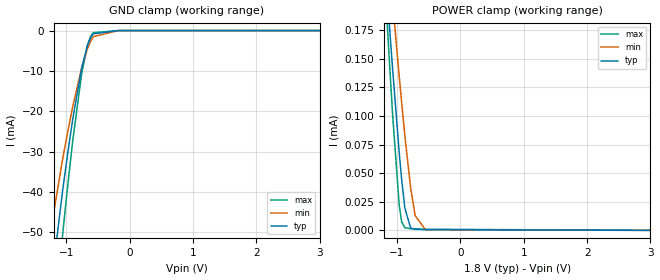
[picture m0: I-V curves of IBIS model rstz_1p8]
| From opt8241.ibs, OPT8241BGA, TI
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|   rstz_1p8 Model
[Model]   rstz_1p8
Model_type   Input
Vinl = 0.54
Vinh = 1.26
|   typ   min   max
|   (nom PVT)   (fast PVT)   (slow PVT)
C_comp   2.094e-12   1.903e-12   2.287e-12
[Model spec]
|subparameter
Vinl   0.54   0.51   0.57
Vinh   1.26   1.19   1.33
| Where nom  PVT is Nominal Process, 1.8V, 27C
|   Fast PVT is Strong Process,  1.9V, -40C
|   Slow PVT is Weak Process,   1.7V, 125C
[Voltage Range]   1.8   1.7   1.9
|Junction Temperature
[Temperature Range]   27   125   -40
[Power Clamp Reference]   1.8   1.7   1.9
[GND Clamp Reference]   0   0   0
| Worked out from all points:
|   GND clamp passes 1 mA (typ) near -0.58 V on its own axis
[GND Clamp]
|   Voltage   I(typ)   I(min)   I(max)
-1.8V     -235.1mA   -133.1mA   -339.3mA
-1.305V   -71.83mA   -55.34mA   -91.7mA
-1.063V   -40.55mA   -32.52mA   -51.65mA
-1.044V   -38.27mA   -30.86mA   -48.69mA
-973.8mV  -30.2mA    -24.94mA   -38.14mA
-896.4mV  -21.94mA   -18.83mA   -27.26mA
-756mV    -9.362mA   -9.239mA   -10.69mA
-665.7mV  -3.75mA    -4.562mA   -3.604mA
-613.4mV  -1.737mA   -2.608mA   -1.375mA
-572.4mV  -810.3uA   -1.519mA   -523.9uA
-180mV    -497.4nA   -564.7nA   -770.9nA
3.6V      0A         0A         0A
[POWER Clamp]
|   Voltage   I(typ)   I(min)   I(max)
-1.8V     735.1uA    693.3uA    857.7uA
-1.206V   246.5uA    288.5uA    232.3uA
-1.163V   212.5uA    260.1uA    189.5uA
-1.122V   180.7uA    233.3uA    149.7uA
-1.069V   141uA      199.5uA    100.9uA
-964.8mV  67.65uA    134.4uA    21.86uA
-926mV    44.02uA    111.2uA    7.444uA
-874.7mV  19.16uA    81.96uA    2.325uA
-785.1mV  2.297uA    37.3uA     1.574uA
-713.7mV  1.064uA    12.95uA    1.402uA
-550.5mV  726.2nA    684.1nA    1.037uA
3.6V      0A         0A         0A
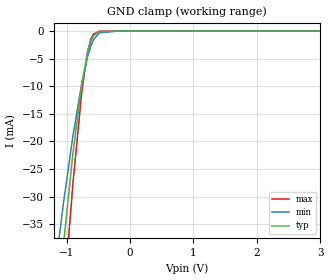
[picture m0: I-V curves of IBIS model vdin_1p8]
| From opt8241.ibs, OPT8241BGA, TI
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|   vdin_1p8 Model
[Model]   vdin_1p8
Model_type   Input
Vinl = 0.54
Vinh = 1.26
|   typ   min   max
|   (nom PVT)   (fast PVT)   (slow PVT)
C_comp   2.094e-12   1.893e-12   2.287e-12
[Model spec]
|subparameter
Vinl   0.54   0.51   0.57
Vinh   1.26   1.19   1.33
| Where nom  PVT is Nominal Process, 1.8V, 27C
|   Fast PVT is Strong Process,  1.9V, -40C
|   Slow PVT is Weak Process,   1.7V, 125C
[Voltage Range]   1.8   1.7   1.9
|Junction Temperature
[Temperature Range]   27   125   -40
[Power Clamp Reference]   1.8   1.7   1.9
[GND Clamp Reference]   0   0   0
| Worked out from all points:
|   GND clamp passes 1 mA (typ) near -0.58 V on its own axis
[GND Clamp]
|   Voltage   I(typ)   I(min)   I(max)
-1.8V     -238.3mA   -133.6mA   -345.3mA
-1.276V   -67.82mA   -52.41mA   -86.62mA
-1.069V   -41.29mA   -33.06mA   -52.62mA
-1.048V   -38.72mA   -31.19mA   -49.28mA
-900mV    -22.3mA    -19.1mA    -27.74mA
-757.8mV  -9.497mA   -9.346mA   -10.86mA
-665.7mV  -3.749mA   -4.562mA   -3.604mA
-615.1mV  -1.787mA   -2.661mA   -1.424mA
-572.4mV  -809.9uA   -1.519mA   -523.2uA
-480.8mV  -92.99uA   -320.3uA   -34.6uA
-180mV    0A         -238.8nA   0A
3.6V      0A         0A         0A
[POWER Clamp]
|   Voltage   I(typ)   I(min)   I(max)
-1.8V     0A         0A         0A
0V        0A         0A         0A
3.6V      0A         0A         0A
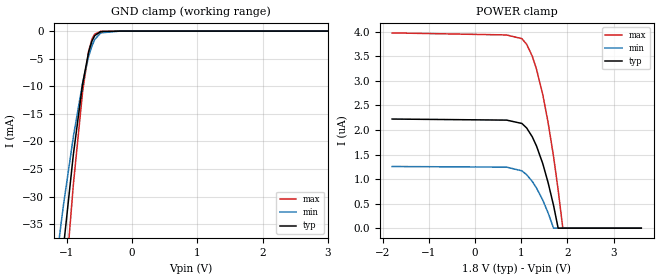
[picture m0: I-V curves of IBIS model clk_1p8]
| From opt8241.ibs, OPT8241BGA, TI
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|   clk_1p8 Model
[Model]   clk_1p8
Model_type   Input
Vinl = 0.54
Vinh = 1.26
|   typ   min   max
|   (nom PVT)   (fast PVT)   (slow PVT)
C_comp   2.106e-12   1.914e-12   2.287e-12
[Model spec]
|subparameter
Vinl   0.54   0.51   0.57
Vinh   1.26   1.19   1.33
| Where nom  PVT is Nominal Process, 1.8V, 27C
|   Fast PVT is Strong Process,  1.9V, -40C
|   Slow PVT is Weak Process,   1.7V, 125C
[Voltage Range]   1.8   1.7   1.9
|Junction Temperature
[Temperature Range]   27   125   -40
[Power Clamp Reference]   1.8   1.7   1.9
[GND Clamp Reference]   0   0   0
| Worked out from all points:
|   GND clamp passes 1 mA (typ) near -0.58 V on its own axis
[GND Clamp]
|   Voltage   I(typ)   I(min)   I(max)
-1.8V     -238.3mA   -133.6mA   -345.3mA
-1.276V   -67.82mA   -52.41mA   -86.63mA
-1.069V   -41.3mA    -33.07mA   -52.62mA
-1.048V   -38.73mA   -31.19mA   -49.28mA
-900mV    -22.31mA   -19.1mA    -27.74mA
-757.8mV  -9.5mA     -9.348mA   -10.87mA
-665.7mV  -3.752mA   -4.563mA   -3.609mA
-615.1mV  -1.79mA    -2.663mA   -1.43mA
-572.4mV  -813uA     -1.52mA    -528.5uA
-480.8mV  -95.75uA   -321.8uA   -39.24uA
-180mV    -948.6nA   -786.6nA   -1.575uA
3.6V      0A         0A         0A
[POWER Clamp]
|   Voltage   I(typ)   I(min)   I(max)
-1.8V     2.223uA    1.256uA    3.978uA
682mV     2.201uA    1.243uA    3.936uA
1.012V    2.133uA    1.168uA    3.86uA
1.115V    2.042uA    1.089uA    3.747uA
1.238V    1.86uA     950.8nA    3.502uA
1.33V     1.671uA    815.9nA    3.236uA
1.466V    1.311uA    568.1nA    2.715uA
1.58V     928.5nA    312.4nA    2.153uA
1.699V    460.9nA    0A         1.457uA
1.798V    0A         0A         779.4nA
1.899V    0A         0A         0A
3.6V      0A         0A         0A
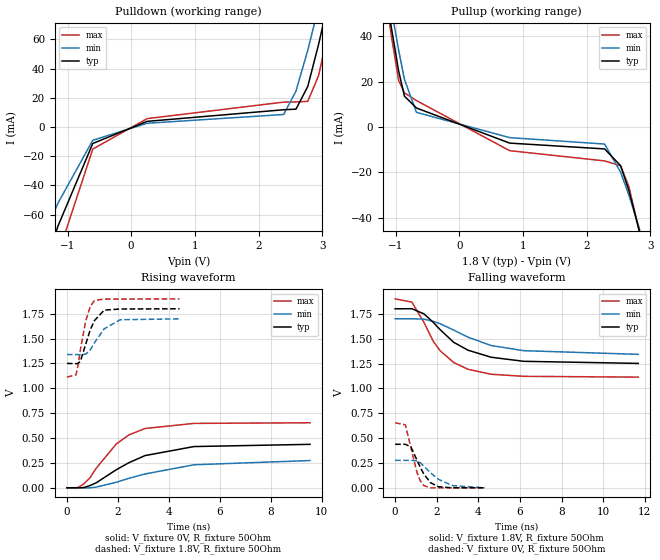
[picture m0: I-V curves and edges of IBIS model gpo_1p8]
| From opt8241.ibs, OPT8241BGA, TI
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|   gpo_1p8 Model
[Model]   gpo_1p8
Model_type   Output
Polarity   Non-Inverting
Vmeas = 0.9
Vref = 0
Cref = 2pF
Rref = 200
|   typ   min   max
|   (nom PVT)   (fast PVT)   (slow PVT)
C_comp   2.206e-12   2.001e-12   2.430e-12
| Where nom  PVT is Nominal Process, 1.8V, 27C
|   Fast PVT is Strong Process,  1.9V, -40C
|   Slow PVT is Weak Process,   1.7V, 125C
[Voltage Range]   1.8   1.7   1.9
|Junction Temperature
[Temperature Range]   27   125   -40
[Pullup Reference]   1.8   1.7   1.9
[Pulldown Reference]   0   0   0
[Power Clamp Reference]   1.8   1.7   1.9
[GND Clamp Reference]   0   0   0
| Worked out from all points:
|   slope of the pulldown table from 0 to 0.27 V, typ, clamps not added: 64.6 ohm
|   slope of the pullup table from 0 to 0.27 V, typ, clamps not added: 92.4 ohm
|   falling waveform, V_fixture 1.8V, R_fixture 50Ohm: 20-80 % time 2.08ns typ, 2.63ns min, 1.53ns max; typ from 1.8 V to 1.25 V
|   rising waveform, V_fixture 0V, R_fixture 50Ohm: 20-80 % time 2ns typ, 2.68ns min, 1.39ns max; typ from 0 V to 0.437 V
|   rising waveform, V_fixture 1.8V, R_fixture 50Ohm: 20-80 % time 451ps typ, 613ps min, 346ps max; typ from 1.25 V to 1.8 V
|   falling waveform, V_fixture 0V, R_fixture 50Ohm: 20-80 % time 641ps typ, 956ps min, 455ps max; typ from 0.437 V to 0 V
[Pulldown]
|   Voltage   I(typ)   I(min)   I(max)
-1.8V     -225.4mA   -143.8mA   -304.1mA
-1.47V    -113.7mA   -86.18mA   -142.8mA
-1.256V   -82.56mA   -62.97mA   -105.6mA
-1.152V   -68.03mA   -52.26mA   -87.72mA
-603.2mV  -11.23mA   -9.042mA   -15.07mA
250.2mV   3.907mA    2.602mA    5.787mA
2.394V    11.86mA    8.618mA    17.09mA
2.588V    12.27mA    24.6mA     17.22mA
2.773V    27.78mA    52.65mA    17.61mA
2.942V    56.45mA    82.16mA    35.09mA
3.07V     80.77mA    105mA      60.11mA
3.6V      185.5mA    195.8mA    177.6mA
[Pullup]
|   Voltage   I(typ)   I(min)   I(max)
-1.8V     185.8mA    179.6mA    199.1mA
-1.134V   55.78mA    63.3mA     53.53mA
-1.067V   43.59mA    51.95mA    39.88mA
-954.5mV  24.76mA    33.93mA    20.59mA
-863.3mV  13.65mA    21.05mA    15.1mA
-674.6mV  8.417mA    6.495mA    11.69mA
789.1mV   -7.076mA   -4.658mA   -10.42mA
2.28V     -9.646mA   -7.498mA   -14.93mA
2.531V    -17.04mA   -19.87mA   -17.07mA
2.661V    -27.87mA   -29.99mA   -26.17mA
2.828V    -46.12mA   -44.98mA   -46.37mA
3.6V      -218.4mA   -181.2mA   -239mA
[Ramp]
R_load = 50
|   typ   min   max
dV/dt_r   0.262388/2.00011e-09   0.165723/2.72562e-09  0.392287/1.3872e-09
dV/dt_f   0.329703/2.07923e-09   0.21601/2.64824e-09   0.472263/1.5328e-09
[Falling Waveform]
V_fixture = 1.8V
V_fixture_min = 1.7V
V_fixture_max = 1.9V
R_fixture = 50Ohm
|   Time   V(typ)   V(min)   V(max)
0s        1.8V       1.7V       1.9V
805ps     1.801V     1.7V       1.867V
1.385ns   1.749V     1.696V     1.663V
1.835ns   1.663V     1.674V     1.472V
2.16ns    1.591V     1.65V      1.379V
2.815ns   1.463V     1.586V     1.26V
3.5ns     1.384V     1.515V     1.192V
4.615ns   1.313V     1.431V     1.142V
6.175ns   1.272V     1.379V     1.121V
11.69ns   1.251V     1.342V     1.113V
[Rising Waveform]
V_fixture = 0V
V_fixture_min = 0V
V_fixture_max = 0V
R_fixture = 50Ohm
|   Time   V(typ)   V(min)   V(max)
0s        442pV      24.69nV    234.8pV
410ps     -532uV     139.8uV    196.7uV
655ps     1.711mV    -589.5uV   36.51mV
905ps     22.11mV    -933uV     99.63mV
1.145ns   49.02mV    6.045mV    194.9mV
1.935ns   180.6mV    55.02mV    439.4mV
2.43ns    251.8mV    94.54mV    531.2mV
3.07ns    323.8mV    138.8mV    596.2mV
4.99ns    414.4mV    231.2mV    647.4mV
9.55ns    436.8mV    273.8mV    653.7mV
[Rising Waveform]
V_fixture = 1.8V
V_fixture_min = 1.7V
V_fixture_max = 1.9V
R_fixture = 50Ohm
|   Time   V(typ)   V(min)   V(max)
0s        1.251V     1.34V      1.113V
355ps     1.248V     1.34V      1.136V
435ps     1.25V      1.339V     1.229V
530ps     1.274V     1.338V     1.391V
740ps     1.446V     1.344V     1.68V
920ps     1.592V     1.388V     1.826V
1.085ns   1.683V     1.46V      1.884V
1.465ns   1.787V     1.599V     1.898V
2.095ns   1.798V     1.69V      1.898V
4.425ns   1.8V       1.699V     1.9V
[Falling Waveform]
V_fixture = 0V
V_fixture_min = 0V
V_fixture_max = 0V
R_fixture = 50Ohm
|   Time   V(typ)   V(min)   V(max)
0s        437.3mV    276.2mV    654mV
490ps     437.9mV    276.1mV    633.4mV
755ps     410.7mV    276.7mV    405.8mV
1.05ns    277.9mV    271.4mV    154.6mV
1.205ns   207.5mV    251.7mV    71.52mV
1.37ns    141.6mV    219.3mV    23.76mV
1.695ns   52.25mV    152.1mV    -395.4uV
2.085ns   10.12mV    85.17mV    -408.6uV
2.75ns    108.6uV    21.92mV    405.3uV
4.3ns     201.7uV    434.8uV    43.6uV
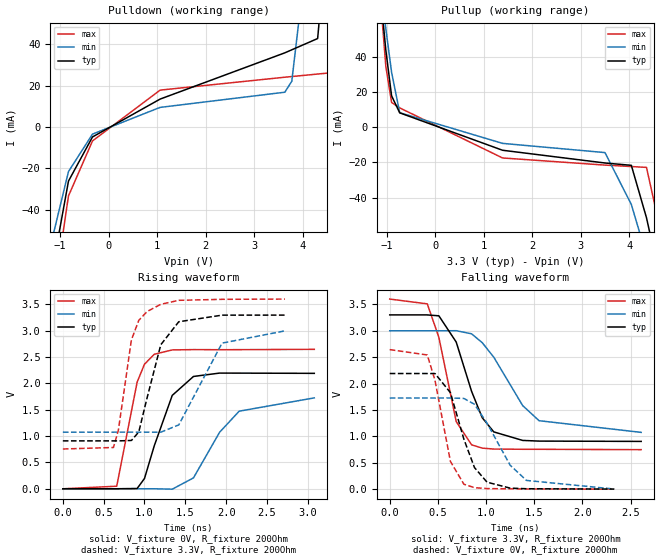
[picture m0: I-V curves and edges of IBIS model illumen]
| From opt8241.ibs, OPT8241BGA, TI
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|   illumen Model
[Model]   illumen
Model_type   Output
Polarity   Non-Inverting
Vmeas = 1.65
Vref = 0
Cref = 2pF
Rref = 200
|   typ   min   max
|   (nom PVT)   (fast PVT)   (slow PVT)
C_comp   2.058e-12   1.793e-12   2.300e-12
| Where nom  PVT is Nominal Process, 3.3V, 27C
|   Fast PVT is Strong Process,  3.6V, -40C
|   Slow PVT is Weak Process,   3V, 125C
[Voltage Range]   3.3   3   3.6
|Junction Temperature
[Temperature Range]   27   125   -40
[Pullup Reference]   3.3   3   3.6
[Pulldown Reference]   0   0   0
[Power Clamp Reference]   3.3   3   3.6
[GND Clamp Reference]   0   0   0
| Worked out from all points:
|   slope of the pulldown table from 0 to 0.495 V, typ, clamps not added: 71.8 ohm
|   slope of the pullup table from 0 to 0.495 V, typ, clamps not added: 95.4 ohm
|   falling waveform, V_fixture 3.3V, R_fixture 200Ohm: 20-80 % time 270ps typ, 406ps min, 197ps max; typ from 3.3 V to 0.906 V
|   rising waveform, V_fixture 0V, R_fixture 200Ohm: 20-80 % time 280ps typ, 430ps min, 194ps max; typ from 0 V to 2.19 V
|   rising waveform, V_fixture 3.3V, R_fixture 200Ohm: 20-80 % time 240ps typ, 348ps min, 179ps max; typ from 0.908 V to 3.29 V
|   falling waveform, V_fixture 0V, R_fixture 200Ohm: 20-80 % time 227ps typ, 330ps min, 166ps max; typ from 2.19 V to 0.004 V
[Pulldown]
|   Voltage   I(typ)   I(min)   I(max)
-3.3V     -1.429A    -1.241A    -1.581A
-1.722V   -185.3mA   -117.5mA   -268.3mA
-1.468V   -109.3mA   -83.9mA    -135.8mA
-825mV    -26.11mA   -21.5mA    -33.3mA
-330mV    -4.75mA    -3.377mA   -6.679mA
1.063V    13.57mA    9.553mA    17.91mA
3.633V    35.95mA    16.9mA     24.16mA
3.777V    37.42mA    22.19mA    24.48mA
4.31V     42.88mA    128.7mA    25.69mA
4.598V    119mA      196mA      26.34mA
4.97V     224.1mA    280.8mA    146.2mA
6.6V      699.7mA    673.8mA    732.4mA
[Pullup]
|   Voltage   I(typ)   I(min)   I(max)
-3.3V     703.4mA    604.2mA    845.2mA
-1.77V    257.9mA    235.9mA    294.5mA
-1.021V   43.73mA    55.8mA     34.52mA
-902.4mV  17.79mA    31.19mA    14.01mA
-735mV    8.123mA    8.213mA    10.94mA
1.384V    -13.14mA   -9.229mA   -17.52mA
3.495V    -20.38mA   -14.47mA   -21.58mA
4.038V    -21.71mA   -43.96mA   -22.4mA
4.35V     -51.47mA   -72.96mA   -22.88mA
4.608V    -83.59mA   -100.1mA   -54.87mA
4.811V    -111.2mA   -149.2mA   -86.36mA
6.6V      -1.426A    -1.474A    -1.322A
[Ramp]
R_load = 200
|   typ   min   max
dV/dt_r   1.3166/2.81454e-10   1.03727/4.30517e-10   1.58757/1.94145e-10
dV/dt_f   1.44014/2.70555e-10   1.15809/4.07283e-10   1.71258/1.97067e-10
[Falling Waveform]
V_fixture = 3.3V
V_fixture_min = 3V
V_fixture_max = 3.6V
R_fixture = 200Ohm
|   Time   V(typ)   V(min)   V(max)
0s        3.3V       3V         3.6V
390ps     3.3V       3V         3.509V
510ps     3.283V     3V         2.876V
690ps     2.787V     3.001V     1.282V
850ps     1.852V     2.942V     841.3mV
960ps     1.355V     2.775V     779mV
1.08ns    1.086V     2.5V       761.2mV
1.38ns    924.6mV    1.584V     757.1mV
1.55ns    911.9mV    1.298V     756.6mV
2.61ns    906mV      1.077V     749.9mV
[Rising Waveform]
V_fixture = 0V
V_fixture_min = 0V
V_fixture_max = 0V
R_fixture = 200Ohm
|   Time   V(typ)   V(min)   V(max)
0s        1.275nV    35.58nV    828.6pV
660ps     290.9uV    -5.246uV   48.7mV
910ps     5.607mV    39.74uV    2.022V
1ns       195.2mV    181.8uV    2.362V
1.12ns    815.7mV    211.7uV    2.55V
1.34ns    1.77V      -7.438mV   2.632V
1.6ns     2.129V     206.2mV    2.638V
1.92ns    2.193V     1.071V     2.636V
2.16ns    2.192V     1.471V     2.637V
3.08ns    2.188V     1.723V     2.643V
[Rising Waveform]
V_fixture = 3.3V
V_fixture_min = 3V
V_fixture_max = 3.6V
R_fixture = 200Ohm
|   Time   V(typ)   V(min)   V(max)
0s        907.9mV    1.073V     753.9mV
620ps     907.9mV    1.073V     782.8mV
680ps     907.6mV    1.074V     1.111V
840ps     915.9mV    1.074V     2.824V
930ps     1.077V     1.073V     3.192V
1.03ns    1.713V     1.073V     3.358V
1.2ns     2.731V     1.073V     3.497V
1.42ns    3.166V     1.211V     3.572V
1.95ns    3.291V     2.761V     3.591V
2.72ns    3.292V     2.993V     3.596V
[Falling Waveform]
V_fixture = 0V
V_fixture_min = 0V
V_fixture_max = 0V
R_fixture = 200Ohm
|   Time   V(typ)   V(min)   V(max)
0s        2.191V     1.727V     2.643V
390ps     2.191V     1.727V     2.542V
470ps     2.19V      1.727V     2.06V
630ps     1.829V     1.728V     526.8mV
770ps     946.4mV    1.719V     95.53mV
880ps     410.2mV    1.608V     30.04mV
1.01ns    134.1mV    1.251V     13.25mV
1.25ns    21.64mV    455.2mV    8.17mV
1.42ns    10.27mV    167.3mV    6.629mV
2.33ns    3.728mV    4.662mV    2.085mV
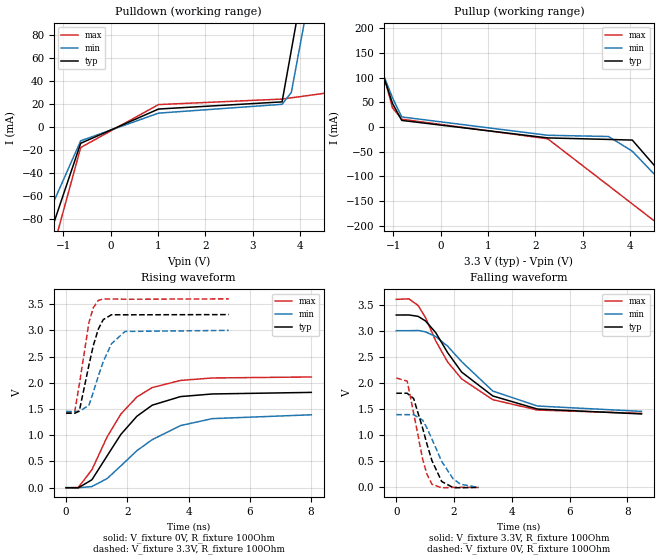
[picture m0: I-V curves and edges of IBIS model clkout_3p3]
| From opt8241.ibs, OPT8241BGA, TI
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|   clkout_3p3 Model
[Model]   clkout_3p3
Model_type   Output
Polarity   Non-Inverting
Vmeas = 1.65
Vref = 0
Cref = 2pF
Rref = 150
|   typ   min   max
|   (nom PVT)   (fast PVT)   (slow PVT)
C_comp   2.130e-12   1.914e-12   2.371e-12
| Where nom  PVT is Nominal Process, 3.3V, 27C
|   Fast PVT is Strong Process,  3.6V, -40C
|   Slow PVT is Weak Process,   3V, 125C
[Voltage Range]   3.3   3   3.6
|Junction Temperature
[Temperature Range]   27   125   -40
[Pullup Reference]   3.3   3   3.6
[Pulldown Reference]   0   0   0
[Power Clamp Reference]   3.3   3   3.6
[GND Clamp Reference]   0   0   0
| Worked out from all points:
|   slope of the pulldown table from 0 to 0.495 V, typ, clamps not added: 56.5 ohm
|   slope of the pullup table from 0 to 0.495 V, typ, clamps not added: 70.7 ohm
|   falling waveform, V_fixture 3.3V, R_fixture 100Ohm: 20-80 % time 1.81ns typ, 1.81ns min, 1.67ns max; typ from 3.3 V to 1.41 V
|   rising waveform, V_fixture 0V, R_fixture 100Ohm: 20-80 % time 1.4ns typ, 1.87ns min, 1.32ns max; typ from 0 V to 1.82 V
|   rising waveform, V_fixture 3.3V, R_fixture 100Ohm: 20-80 % time 426ps typ, 570ps min, 344ps max; typ from 1.42 V to 3.3 V
|   falling waveform, V_fixture 0V, R_fixture 100Ohm: 20-80 % time 571ps typ, 712ps min, 448ps max; typ from 1.8 V to 0.002 V
[Pulldown]
|   Voltage   I(typ)   I(min)   I(max)
-3.3V     -1.592A    -1.388A    -1.755A
-1.956V   -380.3mA   -251.2mA   -493.8mA
-1.791V   -245.8mA   -147.4mA   -346.5mA
-1.656V   -157.1mA   -111.1mA   -233.4mA
-1.478V   -116.7mA   -90.12mA   -144.7mA
-632.4mV  -14.03mA   -11.87mA   -17.7mA
1.013V    15.62mA    12.07mA    19.46mA
3.623V    21.8mA     19.71mA    24.24mA
3.819V    66.55mA    30mA       25.33mA
4.606V    246.5mA    203.8mA    29.72mA
4.926V    319.8mA    281mA      133.7mA
6.6V      702.8mA    676.6mA    735.9mA
[Pullup]
|   Voltage   I(typ)   I(min)   I(max)
-3.3V     708.8mA    609.8mA    850.9mA
-1.021V   47.98mA    59.48mA    39.08mA
-825mV    13.5mA     20.52mA    15.93mA
2.26V     -21.98mA   -16.61mA   -23.78mA
3.546V    -25.06mA   -19.17mA   -118.8mA
4.047V    -26.41mA   -48.96mA   -155.9mA
4.623V    -90.04mA   -106.8mA   -198.5mA
4.737V    -105.5mA   -126.8mA   -206.9mA
4.851V    -122mA     -179.2mA   -215.3mA
4.917V    -136.1mA   -222.6mA   -220.2mA
5.092V    -240.3mA   -354.5mA   -233.1mA
6.6V      -1.589A    -1.651A    -1.466A
[Ramp]
R_load = 100
|   typ   min   max
dV/dt_r   1.08948/1.39353e-09   0.83861/1.88597e-09   1.26613/1.31948e-09
dV/dt_f   1.13769/1.81666e-09   0.931834/1.82974e-09   1.30827/1.66723e-09
[Falling Waveform]
V_fixture = 3.3V
V_fixture_min = 3V
V_fixture_max = 3.6V
R_fixture = 100Ohm
|   Time   V(typ)   V(min)   V(max)
0s        3.3V       3V         3.6V
436ps     3.301V     3V         3.609V
754ps     3.275V     3.005V     3.483V
1.01ns    3.187V     2.978V     3.253V
1.364ns   2.964V     2.887V     2.805V
1.776ns   2.581V     2.705V     2.402V
2.262ns   2.208V     2.407V     2.078V
3.34ns    1.751V     1.845V     1.68V
4.882ns   1.501V     1.559V     1.482V
8.484ns   1.407V     1.456V     1.418V
[Rising Waveform]
V_fixture = 0V
V_fixture_min = 0V
V_fixture_max = 0V
R_fixture = 100Ohm
|   Time   V(typ)   V(min)   V(max)
0s        867.6pV    33.8nV     522.3pV
398ps     -2.799mV   105.7uV    3.906mV
844ps     151.8mV    21.8mV     343.2mV
1.342ns   609.2mV    174.7mV    971.5mV
1.79ns    1.017V     417.2mV    1.405V
2.312ns   1.362V     705.4mV    1.73V
2.812ns   1.573V     916.1mV    1.909V
3.736ns   1.737V     1.184V     2.045V
4.774ns   1.787V     1.317V     2.092V
8.008ns   1.817V     1.39V      2.111V
[Rising Waveform]
V_fixture = 3.3V
V_fixture_min = 3V
V_fixture_max = 3.6V
R_fixture = 100Ohm
|   Time   V(typ)   V(min)   V(max)
0s        1.42V      1.454V     1.431V
282ps     1.419V     1.454V     1.453V
432ps     1.462V     1.454V     1.966V
748ps     2.343V     1.574V     3.154V
890ps     2.712V     1.822V     3.434V
1.054ns   3.025V     2.132V     3.571V
1.214ns   3.205V     2.404V     3.599V
1.482ns   3.297V     2.745V     3.598V
1.926ns   3.296V     2.979V     3.593V
5.312ns   3.3V       2.999V     3.6V
[Falling Waveform]
V_fixture = 0V
V_fixture_min = 0V
V_fixture_max = 0V
R_fixture = 100Ohm
|   Time   V(typ)   V(min)   V(max)
0s        1.803V     1.394V     2.095V
376ps     1.803V     1.394V     2.035V
600ps     1.704V     1.394V     1.424V
916ps     1.128V     1.287V     534.8mV
1.064ns   824.8mV    1.136V     249.5mV
1.234ns   514mV      926mV      61.55mV
1.572ns   114.6mV    497.5mV    -6.876mV
1.974ns   -3.272mV   159.8mV    2.209mV
2.234ns   -4.865mV   60.08mV    2.876mV
2.856ns   2.118mV    1.553mV    1.05mV
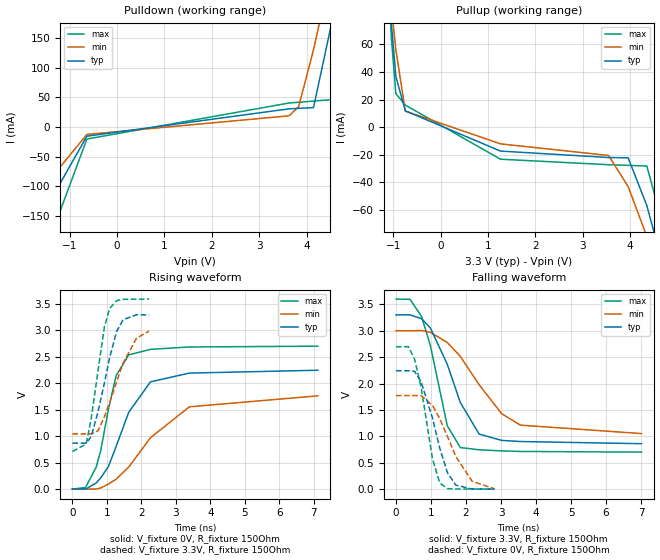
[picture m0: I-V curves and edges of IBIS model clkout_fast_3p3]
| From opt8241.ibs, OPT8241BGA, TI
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|   clkout_fast_3p3 Model
[Model]   clkout_fast_3p3
Model_type   Output
Polarity   Non-Inverting
Vmeas = 1.65
Vref  = 0
Cref  = 2pF
Rref  = 150
|   typ   min   max
|   (nom PVT)   (fast PVT)   (slow PVT)
C_comp   2.118e-12   1.852e-12   2.357e-12
| Where nom  PVT is Nominal Process, 3.3V, 27C
|   Fast PVT is Strong Process,  3.6V, -40C
|   Slow PVT is Weak Process,   3V, 125C
[Voltage Range]   3.3   3   3.6
|Junction Temperature
[Temperature Range]   27   125   -40
[Pullup Reference]   3.3   3   3.6
[Pulldown Reference]   0   0   0
[Power Clamp Reference]   3.3   3   3.6
[GND Clamp Reference]   0   0   0
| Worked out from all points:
|   slope of the pulldown table from 0 to 0.495 V, typ, clamps not added: 50.4 ohm
|   slope of the pullup table from 0 to 0.495 V, typ, clamps not added: 66.6 ohm
|   falling waveform, V_fixture 3.3V, R_fixture 150Ohm: 20-80 % time 837ps typ, 1.28ns min, 568ps max; typ from 3.3 V to 0.861 V
|   rising waveform, V_fixture 0V, R_fixture 150Ohm: 20-80 % time 854ps typ, 1.43ns min, 525ps max; typ from 0 V to 2.25 V
|   rising waveform, V_fixture 3.3V, R_fixture 150Ohm: 20-80 % time 503ps typ, 643ps min, 383ps max; typ from 0.867 V to 3.29 V
|   falling waveform, V_fixture 0V, R_fixture 150Ohm: 20-80 % time 537ps typ, 727ps min, 404ps max; typ from 2.24 V to 0.002 V
[Pulldown]
|   Voltage   I(typ)   I(min)   I(max)
-3.3V     -1.689A    -1.476A    -1.859A
-1.953V   -392.4mA   -256.2mA   -511.3mA
-1.741V   -212.5mA   -128.9mA   -311.9mA
-1.659V   -159.5mA   -111.9mA   -240mA
-636mV    -15.24mA   -12.29mA   -20.09mA
3.633V    30.87mA    19.13mA    40.69mA
3.834V    31.66mA    34.57mA    41.97mA
4.148V    32.91mA    130.4mA    43.97mA
4.498V    163.3mA    256.7mA    46.19mA
4.616V    207.6mA    300.7mA    46.95mA
4.831V    315.1mA    380.5mA    188.6mA
6.6V      1.225A     1.047A     1.541A
[Pullup]
|   Voltage   I(typ)   I(min)   I(max)
-3.3V     1.23A      937mA      1.78A
-1.241V   171.9mA    160.5mA    203.9mA
-1.039V   75.18mA    87.58mA    64.89mA
-943.8mV  36.69mA    56.01mA    24.26mA
-744mV    11.82mA    11.62mA    15.98mA
1.265V    -17.34mA   -12.11mA   -23.22mA
3.546V    -22mA      -20.51mA   -27.21mA
3.96V     -22.24mA   -43.08mA   -27.69mA
4.354V    -56.84mA   -79.17mA   -28.16mA
4.633V    -92.1mA    -109mA     -63.38mA
4.854V    -123.2mA   -184.5mA   -98.16mA
6.6V      -1.686A    -1.757A    -1.55A
[Ramp]
R_load = 150
|   typ   min   max
dV/dt_r   1.34763/8.49556e-10   1.06462/1.44006e-09   1.6209/5.23383e-10
dV/dt_f   1.46281/8.32433e-10   1.17593/1.29164e-09   1.73841/5.67517e-10
[Falling Waveform]
V_fixture = 3.3V
V_fixture_min = 3V
V_fixture_max = 3.6V
R_fixture = 150Ohm
|   Time   V(typ)   V(min)   V(max)
0s        3.3V       3V         3.6V
402ps     3.3V       3V         3.595V
730ps     3.229V     3.004V     3.271V
982ps     3.053V     2.97V      2.721V
1.464ns   2.366V     2.779V     1.202V
1.838ns   1.64V      2.514V     787.6mV
2.376ns   1.043V     1.977V     746mV
3.018ns   923.9mV    1.429V     724.8mV
3.552ns   902.4mV    1.213V     714.4mV
7.012ns   861.2mV    1.053V     701.8mV
[Rising Waveform]
V_fixture = 0V
V_fixture_min = 0V
V_fixture_max = 0V
R_fixture = 150Ohm
|   Time   V(typ)   V(min)   V(max)
0s        866pV      37.5nV     485.6pV
380ps     -2.069mV   74.2uV     29.51mV
688ps     113.4mV    1.185mV    412.7mV
820ps     211mV      20.32mV    723.1mV
1.044ns   425.6mV    93.91mV    1.507V
1.268ns   805.2mV    187.8mV    2.146V
1.634ns   1.453V     416.4mV    2.538V
2.266ns   2.028V     971.7mV    2.642V
3.392ns   2.193V     1.555V     2.687V
7.122ns   2.247V     1.763V     2.702V
[Rising Waveform]
V_fixture = 3.3V
V_fixture_min = 3V
V_fixture_max = 3.6V
R_fixture = 150Ohm
|   Time   V(typ)   V(min)   V(max)
0s        867.4mV    1.042V     709.9mV
400ps     868.2mV    1.042V     851.9mV
546ps     997.1mV    1.042V     1.338V
742ps     1.463V     1.102V     2.234V
926ps     2V         1.361V     3.061V
1.078ns   2.483V     1.631V     3.413V
1.284ns   2.981V     2.033V     3.564V
1.47ns    3.203V     2.382V     3.588V
1.862ns   3.296V     2.856V     3.59V
2.226ns   3.292V     2.986V     3.593V
[Falling Waveform]
|Gnd
V_fixture = 0V
V_fixture_min = 0V
V_fixture_max = 0V
R_fixture = 150Ohm
|   Time   V(typ)   V(min)   V(max)
0s        2.243V     1.773V     2.697V
356ps     2.243V     1.773V     2.698V
532ps     2.231V     1.773V     2.46V
718ps     2.034V     1.772V     1.931V
1.044ns   1.343V     1.582V     568mV
1.25ns    776.9mV    1.336V     117.7mV
1.47ns    311.6mV    999.4mV    11.76mV
1.71ns    76.63mV    618.4mV    3.088mV
2.174ns   180.1uV    148.7mV    3.569mV
2.82ns    2.205mV    7.394mV    1.471mV
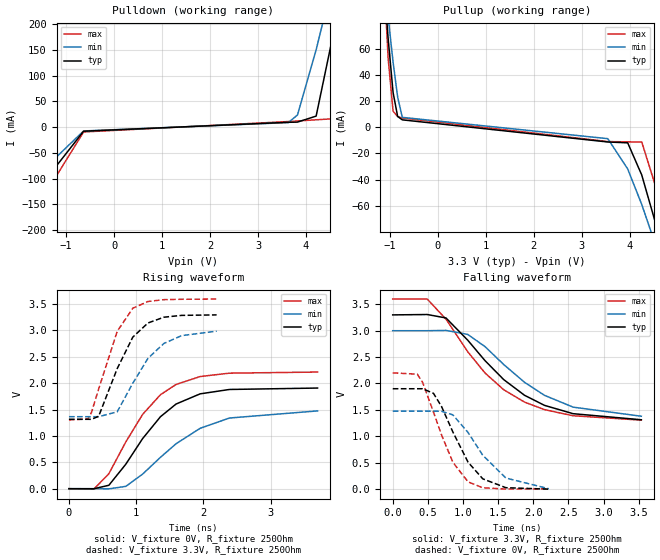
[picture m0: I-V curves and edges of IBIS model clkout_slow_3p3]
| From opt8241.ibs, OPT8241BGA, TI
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|   clkout_slow_3p3 Model
[Model]   clkout_slow_3p3
Model_type   Output
Polarity   Non-Inverting
Vmeas = 1.65
Vref  = 0
Cref  = 2pF
Rref  = 350
|   typ   min   max
|   (nom PVT)   (fast PVT)   (slow PVT)
C_comp   2.143e-12   1.924e-12   2.371e-12
| Where nom  PVT is Nominal Process, 3.3V, 27C
|   Fast PVT is Strong Process,  3.6V, -40C
|   Slow PVT is Weak Process,   3V, 125C
[Voltage Range]   3.3   3   3.6
|Junction Temperature
[Temperature Range]   27   125   -40
[Pullup Reference]   3.3   3   3.6
[Pulldown Reference]   0   0   0
[Power Clamp Reference]   3.3   3   3.6
[GND Clamp Reference]   0   0   0
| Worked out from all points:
|   slope of the pulldown table from 0 to 0.495 V, typ, clamps not added: 125 ohm
|   slope of the pullup table from 0 to 0.495 V, typ, clamps not added: 158 ohm
|   falling waveform, V_fixture 3.3V, R_fixture 250Ohm: 20-80 % time 948ps typ, 938ps min, 914ps max; typ from 3.3 V to 1.31 V
|   rising waveform, V_fixture 0V, R_fixture 250Ohm: 20-80 % time 706ps typ, 901ps min, 688ps max; typ from 0 V to 1.91 V
|   rising waveform, V_fixture 3.3V, R_fixture 250Ohm: 20-80 % time 407ps typ, 489ps min, 364ps max; typ from 1.31 V to 3.29 V
|   falling waveform, V_fixture 0V, R_fixture 250Ohm: 20-80 % time 433ps typ, 501ps min, 381ps max; typ from 1.9 V to -0.004 V
[Pulldown]
|   Voltage   I(typ)   I(min)   I(max)
-3.3V     -1.691A    -1.478A    -1.861A
-1.947V   -381.2mA   -244.1mA   -503.6mA
-1.792V   -245mA     -141mA     -353mA
-1.671V   -157.8mA   -105.8mA   -243.4mA
-1.471V   -107.1mA   -81.93mA   -135mA
-636mV    -7.898mA   -7.402mA   -9.376mA
3.633V    9.393mA    8.858mA    10.86mA
3.822V    9.781mA    23.62mA    11.96mA
4.211V    21.42mA    150mA      14.23mA
4.559V    176.5mA    281.6mA    16.25mA
4.872V    338.5mA    400.1mA    217.8mA
6.6V      1.23A      1.05A      1.546A
[Pullup]
|   Voltage   I(typ)   I(min)   I(max)
-3.3V     1.231A     937.1mA    1.781A
-1.241V   167.8mA    159.4mA    197mA
-1.036V   67.55mA    83.98mA    52.58mA
-933mV    26.45mA    49.6mA     12.19mA
-838.2mV  8.16mA     23mA       8.174mA
-741mV    5.564mA    7.463mA    6.938mA
3.543V    -11.34mA   -8.805mA   -11mA
3.957V    -11.96mA   -31.91mA   -11.23mA
4.25V     -36.54mA   -59.01mA   -11.38mA
4.63V     -85.02mA   -99.87mA   -55.84mA
4.829V    -113.8mA   -160.6mA   -88.71mA
6.6V      -1.69A     -1.76A     -1.556A
[Ramp]
R_load = 250
|   typ   min   max
dV/dt_r   1.14461/7.03914e-10   0.886664/9.02287e-10   1.32636/6.87359e-10
dV/dt_f   1.19792/9.5394e-10   0.98429/9.56025e-10   1.38497/9.2458e-10
[Falling Waveform]
V_fixture = 3.3V
V_fixture_min = 3V
V_fixture_max = 3.6V
R_fixture = 250Ohm
|   Time   V(typ)   V(min)   V(max)
0s        3.3V       3V         3.6V
492ps     3.307V     3V         3.599V
758ps     3.242V     3.006V     3.219V
1.068ns   2.82V      2.93V      2.601V
1.314ns   2.432V     2.698V     2.198V
1.58ns    2.073V     2.359V     1.881V
1.876ns   1.776V     2.022V     1.647V
2.16ns    1.585V     1.775V     1.504V
2.568ns   1.427V     1.551V     1.388V
3.538ns   1.312V     1.379V     1.305V
[Rising Waveform]
V_fixture = 0V
V_fixture_min = 0V
V_fixture_max = 0V
R_fixture = 250Ohm
|   Time   V(typ)   V(min)   V(max)
0s        2.931nV    121nV      1.671nV
370ps     -1.212mV   69.73uV    -9.012mV
594ps     64.65mV    -2.611mV   284.5mV
846ps     463.8mV    43.84mV    886.3mV
1.096ns   948.5mV    276.1mV    1.407V
1.362ns   1.364V     594.7mV    1.781V
1.594ns   1.604V     851.3mV    1.975V
1.952ns   1.797V     1.144V     2.125V
2.388ns   1.88V      1.339V     2.189V
3.7ns     1.907V     1.474V     2.21V
[Rising Waveform]
V_fixture = 3.3V
V_fixture_min = 3V
V_fixture_max = 3.6V
R_fixture = 250Ohm
|   Time   V(typ)   V(min)   V(max)
0s        1.315V     1.364V     1.303V
280ps     1.315V     1.364V     1.321V
334ps     1.314V     1.364V     1.44V
442ps     1.372V     1.364V     1.889V
718ps     2.275V     1.457V     2.981V
950ps     2.872V     1.998V     3.419V
1.176ns   3.14V      2.47V      3.547V
1.412ns   3.249V     2.751V     3.582V
1.676ns   3.284V     2.9V       3.589V
2.198ns   3.293V     2.985V     3.593V
[Falling Waveform]
|Gnd
V_fixture = 0V
V_fixture_min = 0V
V_fixture_max = 0V
R_fixture = 250Ohm
|   Time   V(typ)   V(min)   V(max)
0s        1.9V       1.475V     2.201V
350ps     1.9V       1.475V     2.176V
426ps     1.9V       1.475V     2.02V
580ps     1.813V     1.475V     1.458V
694ps     1.565V     1.473V     1.028V
856ps     1.081V     1.405V     506.2mV
1.072ns   508.2mV    1.071V     134.7mV
1.282ns   192mV      638.8mV    22.72mV
1.61ns    24.49mV    207.6mV    -1.395mV
2.222ns   -3.627mV   4.419mV    2.388mV
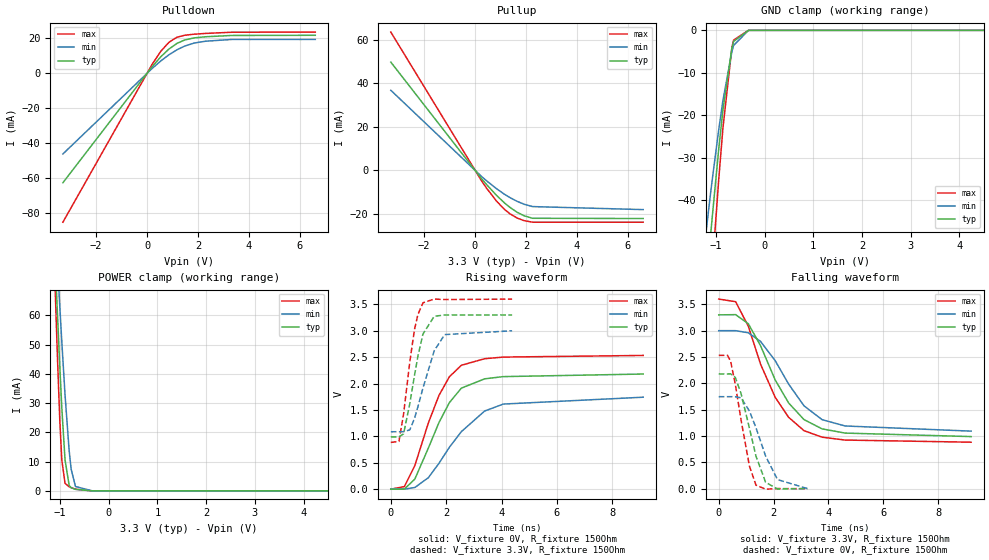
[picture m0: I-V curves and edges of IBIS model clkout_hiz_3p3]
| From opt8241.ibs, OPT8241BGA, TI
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|   clkout_hiz_3p3  Model
[Model]   clkout_hiz_3p3
Model_type   3-state
Polarity   Non-Inverting
Vmeas = 1.65
Vref = 0
Cref = 2pF
Rref = 150
|   typ   min   max
|   (nom PVT)   (fast PVT)   (slow PVT)
C_comp   2.130e-12   1.914e-12   2.371e-12
| Where nom  PVT is Nominal Process, 3.3V, 27C
|   Fast PVT is Strong Process,  3.6V, -40C
|   Slow PVT is Weak Process,   3V, 125C
[Voltage Range]   3.3   3   3.6
|Junction Temperature
[Temperature Range]   27   125   -40
[Pullup Reference]   3.3   3   3.6
[Pulldown Reference]   0   0   0
[Power Clamp Reference]   3.3   3   3.6
[GND Clamp Reference]   0   0   0
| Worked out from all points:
|   slope of the pulldown table from 0 to 0.495 V, typ, clamps not added: 56.5 ohm
|   slope of the pullup table from 0 to 0.495 V, typ, clamps not added: 70.8 ohm
|   POWER clamp passes 1 mA (typ) near -0.76 V on its own axis
|   falling waveform, V_fixture 3.3V, R_fixture 150Ohm: 20-80 % time 1.4ns typ, 1.49ns min, 1.34ns max; typ from 3.3 V to 0.99 V
|   rising waveform, V_fixture 0V, R_fixture 150Ohm: 20-80 % time 1.15ns typ, 1.58ns min, 1.08ns max; typ from 0 V to 2.18 V
|   rising waveform, V_fixture 3.3V, R_fixture 150Ohm: 20-80 % time 481ps typ, 635ps min, 404ps max; typ from 0.991 V to 3.3 V
|   falling waveform, V_fixture 0V, R_fixture 150Ohm: 20-80 % time 610ps typ, 747ps min, 495ps max; typ from 2.18 V to 0.003 V
[Pulldown]
|   Voltage   I(typ)   I(min)   I(max)
-3.3V     -62.74mA   -46.25mA   -85.37mA
206.4mV   3.87mA     2.847mA    5.282mA
537mV     9.429mA    7.033mA    12.56mA
861mV     13.92mA    10.61mA    17.79mA
1.171V    17.1mA     13.45mA    20.65mA
1.473V    19.08mA    15.58mA    21.79mA
1.848V    20.29mA    17.33mA    22.41mA
2.3V      20.95mA    18.4mA     22.85mA
3.324V    21.68mA    19.4mA     23.53mA
6.6V      21.79mA    19.4mA     23.62mA
[GND Clamp]
|   Voltage   I(typ)   I(min)   I(max)
-3.3V     -1.641A    -1.433A    -1.808A
-1.214V   -62.54mA   -48.71mA   -79.99mA
-1.108V   -48.25mA   -38.29mA   -61.64mA
-1.064V   -42.72mA   -34.25mA   -54.47mA
-940.5mV  -27.87mA   -23.35mA   -35.04mA
-855mV    -18.76mA   -16.55mA   -23.01mA
-672mV    -4.274mA   -5.082mA   -4.208mA
-636mV    -2.622mA   -3.546mA   -2.297mA
-330mV    -1.045uA   -12.56uA   -95.92nA
6.6V      0A         0A         0A
[Pullup]
|   Voltage   I(typ)   I(min)   I(max)
-3.3V     49.77mA    36.84mA    63.57mA
252mV     -3.665mA   -2.694mA   -4.646mA
459mV     -6.527mA   -4.79mA    -8.203mA
855mV     -11.56mA   -8.469mA   -14.21mA
1.164V    -14.98mA   -10.99mA   -17.95mA
1.366V    -16.91mA   -12.43mA   -19.87mA
1.657V    -19.23mA   -14.22mA   -21.89mA
1.931V    -20.85mA   -15.53mA   -23.07mA
2.26V     -21.98mA   -16.61mA   -23.78mA
6.6V      -22.1mA    -18mA      -23.78mA
[POWER Clamp]
|   Voltage   I(typ)   I(min)   I(max)
-3.3V     985.5mA    793.3mA    1.299A
-1.122V   87.61mA    99.27mA    81.09mA
-1.086V   73.24mA    87.95mA    62.12mA
-1.049V   59.04mA    76.62mA    43.9mA
-1.005V   42.61mA    63.17mA    24.29mA
-963mV    28.33mA    50.88mA    10.52mA
-897mV    10.62mA    32.8mA     2.616mA
-812.4mV  1.893mA    13.75mA    1.398mA
-771mV    1.105mA    7.398mA    1.104mA
-682.8mV  541.5uA    1.506mA    580.6uA
-330mV    771.2nA    5.113uA    116.9nA
6.6V      0A         0A         0A
[Ramp]
R_load = 150
|   typ   min   max
dV/dt_r   1.30927/1.14921e-09   1.04813/1.58535e-09   1.52033/1.08157e-09
dV/dt_f   1.38832/1.40335e-09   1.14818/1.49284e-09   1.63154/1.34519e-09
[Falling Waveform]
V_fixture = 3.3V
V_fixture_min = 3V
V_fixture_max = 3.6V
R_fixture = 150Ohm
|   Time   V(typ)   V(min)   V(max)
0s        3.3V       3V         3.6V
616ps     3.304V     3V         3.55V
1.078ns   3.132V     2.96V      3.084V
1.526ns   2.713V     2.795V     2.362V
2.058ns   2.064V     2.43V      1.735V
2.548ns   1.627V     1.985V     1.355V
3.108ns   1.312V     1.573V     1.102V
3.766ns   1.136V     1.311V     978.1mV
4.606ns   1.056V     1.191V     923.6mV
9.198ns   989.5mV    1.093V     882.9mV
[Rising Waveform]
V_fixture = 0V
V_fixture_min = 0V
V_fixture_max = 0V
R_fixture = 150Ohm
|   Time   V(typ)   V(min)   V(max)
0s        978.5pV    39.2nV     574.4pV
490ps     1.278mV    -38.54uV   48.82mV
868ps     191.5mV    31.71mV    447.6mV
1.358ns   782.1mV    218.6mV    1.258V
1.736ns   1.259V     487.6mV    1.773V
2.114ns   1.639V     792.7mV    2.128V
2.548ns   1.914V     1.09V      2.347V
3.388ns   2.09V      1.48V      2.471V
4.06ns    2.132V     1.612V     2.502V
9.114ns   2.181V     1.742V     2.533V
[Rising Waveform]
V_fixture = 3.3V
V_fixture_min = 3V
V_fixture_max = 3.6V
R_fixture = 150Ohm
|   Time   V(typ)   V(min)   V(max)
0s        990.9mV    1.088V     885.5mV
294ps     990.7mV    1.088V     905mV
462ps     1.049V     1.088V     1.426V
686ps     1.622V     1.123V     2.414V
854ps     2.15V      1.338V     3.021V
980ps     2.523V     1.563V     3.311V
1.162ns   2.94V      1.918V     3.53V
1.568ns   3.275V     2.623V     3.601V
1.946ns   3.3V       2.928V     3.592V
4.38ns    3.299V     3V         3.6V
[Falling Waveform]
V_fixture = 0V
V_fixture_min = 0V
V_fixture_max = 0V
R_fixture = 150Ohm
|   Time   V(typ)   V(min)   V(max)
0s        2.179V     1.747V     2.532V
322ps     2.179V     1.747V     2.531V
434ps     2.18V      1.747V     2.419V
602ps     2.114V     1.747V     1.991V
812ps     1.809V     1.726V     1.31V
1.12ns    1.147V     1.474V     426.9mV
1.358ns   616.8mV    1.157V     67.13mV
1.708ns   122.9mV    620.1mV    -8.503mV
2.142ns   -5.888mV   173.5mV    2.375mV
3.234ns   2.509mV    2.187mV    764uV
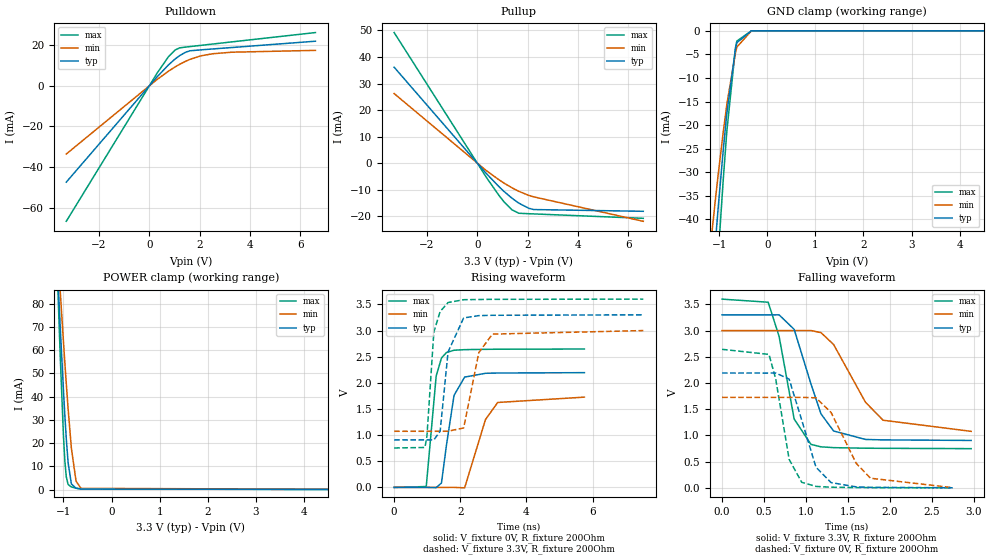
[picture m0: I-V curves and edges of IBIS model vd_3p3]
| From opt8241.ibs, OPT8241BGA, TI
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|   vd_3p3 Model
[Model]   vd_3p3
Model_type   I/O
Polarity   Non-Inverting
Enable   Active-Low
Vinl = 0.99
Vinh = 2.31
Vmeas = 1.65
Vref = 0
Cref = 2pF
Rref = 200
|   typ   min   max
|   (nom PVT)   (fast PVT)   (slow PVT)
C_comp   2.219e-12   1.984e-12   2.430e-12
[Model spec]
|subparameter
Vinl   0.99   0.90   1.08
Vinh   2.31   2.10   2.52
| Where nom  PVT is Nominal Process, 3.3V, 27C
|   Fast PVT is Strong Process,  3.6V, -40C
|   Slow PVT is Weak Process,   3V, 125C
[Voltage Range]   3.3   3   3.6
|Junction Temperature
[Temperature Range]   27   125   -40
[Pullup Reference]   3.3   3   3.6
[Pulldown Reference]   0   0   0
[Power Clamp Reference]   3.3   3   3.6
[GND Clamp Reference]   0   0   0
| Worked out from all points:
|   slope of the pulldown table from 0 to 0.495 V, typ, clamps not added: 71.8 ohm
|   slope of the pullup table from 0 to 0.495 V, typ, clamps not added: 95.4 ohm
|   POWER clamp passes 1 mA (typ) near -0.78 V on its own axis
|   falling waveform, V_fixture 3.3V, R_fixture 200Ohm: 20-80 % time 275ps typ, 410ps min, 200ps max; typ from 3.3 V to 0.905 V
|   rising waveform, V_fixture 0V, R_fixture 200Ohm: 20-80 % time 294ps typ, 443ps min, 204ps max; typ from 0 V to 2.19 V
|   rising waveform, V_fixture 3.3V, R_fixture 200Ohm: 20-80 % time 251ps typ, 366ps min, 190ps max; typ from 0.908 V to 3.3 V
|   falling waveform, V_fixture 0V, R_fixture 200Ohm: 20-80 % time 230ps typ, 339ps min, 168ps max; typ from 2.19 V to 0.003 V
[Pulldown]
|   Voltage   I(typ)   I(min)   I(max)
-3.3V     -47.49mA   -33.64mA   -66.79mA
307.2mV   4.367mA    3.067mA    6.17mA
762mV     10.28mA    7.183mA    14.35mA
1.031V    13.25mA    9.318mA    17.65mA
1.203V    14.84mA    10.55mA    18.67mA
1.441V    16.5mA     12.05mA    19.05mA
1.623V    17.24mA    13.03mA    19.31mA
2.043V    17.67mA    14.72mA    19.89mA
2.521V    18.12mA    15.77mA    20.55mA
3.29V     18.84mA    16.53mA    21.62mA
6.6V      21.94mA    17.43mA    26.2mA
[GND Clamp]
|   Voltage   I(typ)   I(min)   I(max)
-3.3V     -1.435A    -1.247A    -1.587A
-1.188V   -59.19mA   -46.31mA   -75.72mA
-1.093V   -46.61mA   -37.13mA   -59.51mA
-1.023V   -37.77mA   -30.66mA   -48.01mA
-1.021V   -37.55mA   -30.5mA    -47.72mA
-914.1mV  -25.09mA   -21.32mA   -31.35mA
-840mV    -17.39mA   -15.55mA   -21.19mA
-660mV    -3.71mA    -4.587mA   -3.526mA
-632.4mV  -2.514mA   -3.451mA   -2.169mA
-330mV    -1.062uA   -12.81uA   -96.75nA
6.6V      0A         0A         0A
[Pullup]
|   Voltage   I(typ)   I(min)   I(max)
-3.3V     36.16mA    26.24mA    49.2mA
361.2mV   -3.83mA    -2.739mA   -5.255mA
867.9mV   -8.806mA   -6.223mA   -12.12mA
1.063V    -10.56mA   -7.433mA   -14.45mA
1.384V    -13.14mA   -9.229mA   -17.52mA
1.65V     -14.96mA   -10.52mA   -18.79mA
2.043V    -16.9mA    -12.04mA   -18.96mA
2.247V    -17.4mA    -12.62mA   -19.04mA
6.6V      -18.06mA   -21.82mA   -20.7mA
[POWER Clamp]
|   Voltage   I(typ)   I(min)   I(max)
-3.3V     1.113A     867.8mA    1.544A
-1.129V   96.9mA     105.9mA    94.41mA
-1.102V   85.27mA    97.07mA    78.25mA
-1.068V   70.53mA    85.71mA    58.13mA
-999.6mV  42.66mA    63.62mA    23.06mA
-970.2mV  31.75mA    54.47mA    12.19mA
-940.5mV  21.81mA    45.53mA    5.456mA
-903mV    11.6mA     34.81mA    2.221mA
-834.9mV  2.433mA    17.82mA    1.123mA
-738mV    595.3uA    3.664mA    629.8uA
-636mV    257uA      540.1uA    255.4uA
6.6V      0A         0A         0A
[Ramp]
R_load = 200
|   typ   min   max
dV/dt_r   1.316/2.93202e-10   1.03695/4.42937e-10   1.5882/2.03924e-10
dV/dt_f   1.43855/2.75294e-10  1.15718/4.11829e-10   1.71235/2.00086e-10
[Falling Waveform]
V_fixture = 3.3V
V_fixture_min = 3V
V_fixture_max = 3.6V
R_fixture = 200Ohm
|   Time   V(typ)   V(min)   V(max)
0s        3.3V       3V         3.6V
550ps     3.3V       3V         3.541V
680ps     3.301V     3V         2.892V
860ps     3.023V     3V         1.313V
1.06ns    1.983V     3.001V     831.3mV
1.18ns    1.411V     2.961V     783.5mV
1.33ns    1.086V     2.735V     768.2mV
1.71ns    924.7mV    1.634V     757.3mV
1.92ns    916mV      1.291V     755.3mV
2.97ns    905.5mV    1.079V     749.2mV
[Rising Waveform]
V_fixture = 0V
V_fixture_min = 0V
V_fixture_max = 0V
R_fixture = 200Ohm
|   Time   V(typ)   V(min)   V(max)
0s        1.297nV    41.81nV    828.7pV
970ps     -19.32uV   33.83nV    16.48mV
1.27ns    -4.6mV     34.13nV    2.128V
1.43ns    83.91mV    34.82nV    2.474V
1.58ns    805.1mV    -47.5uV    2.578V
1.81ns    1.76V      531uV      2.623V
2.13ns    2.109V     -8.83mV    2.634V
2.76ns    2.182V     1.297V     2.64V
3.13ns    2.187V     1.624V     2.642V
5.75ns    2.194V     1.726V     2.646V
[Rising Waveform]
V_fixture = 3.3V
V_fixture_min = 3V
V_fixture_max = 3.6V
R_fixture = 200Ohm
|   Time   V(typ)   V(min)   V(max)
0s        907.9mV    1.073V     753.9mV
930ps     907.9mV    1.073V     762.9mV
990ps     907.9mV    1.073V     974.1mV
1.2ns     906.7mV    1.073V     2.974V
1.39ns    1.074V     1.073V     3.363V
1.63ns    2.592V     1.074V     3.535V
2.1ns     3.24V      1.137V     3.589V
2.56ns    3.285V     2.579V     3.593V
2.97ns    3.291V     2.931V     3.596V
7.53ns    3.3V       2.999V     3.6V
[Falling Waveform]
V_fixture = 0V
V_fixture_min = 0V
V_fixture_max = 0V
R_fixture = 200Ohm
|   Time   V(typ)   V(min)   V(max)
0s        2.191V     1.727V     2.643V
560ps     2.19V      1.727V     2.546V
640ps     2.191V     1.727V     2.075V
800ps     2.075V     1.727V     544.6mV
950ps     1.293V     1.727V     107.1mV
1.12ns    394.5mV    1.718V     29.04mV
1.3ns     101.6mV    1.439V     13.51mV
1.6ns     19.95mV    468.5mV    7.198mV
1.77ns    11.07mV    185mV      5.807mV
2.75ns    3.203mV    5.813mV    1.421mV
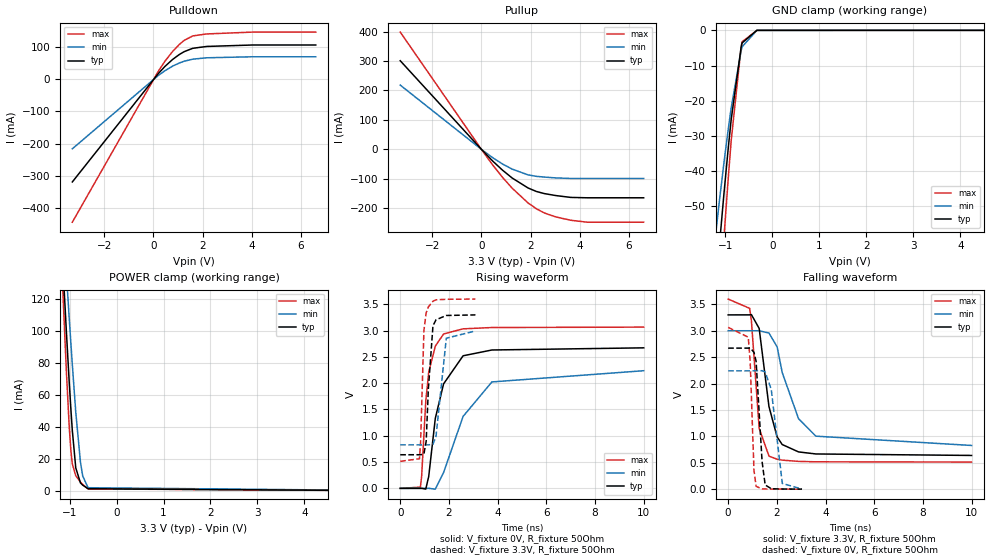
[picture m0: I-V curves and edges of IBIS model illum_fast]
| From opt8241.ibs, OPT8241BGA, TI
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|   illum_fast Model
[Model]   illum_fast
Model_type   I/O
Polarity   Non-Inverting
Enable   Active-High
Vinl  = 0.99
Vinh  = 2.31
Vmeas = 1.65
Vref  = 0
Cref  = 2pF
Rref  = 50
|   typ   min   max
|   (nom PVT)   (fast PVT)   (slow PVT)
C_comp   2.708e-12   2.507e-12   2.914e-12
[Model spec]
|subparameter
Vinl   0.99   0.90   1.08
Vinh   2.31   2.10   2.52
| Where nom  PVT is Nominal Process, 3.3V, 27C
|   Fast PVT is Strong Process,  3.6V, -40C
|   Slow PVT is Weak Process,   3V, 125C
[Voltage Range]   3.3   3   3.6
|Junction Temperature
[Temperature Range]   27   125   -40
[Pullup Reference]   3.3   3   3.6
[Pulldown Reference]   0   0   0
[Power Clamp Reference]   3.3   3   3.6
[GND Clamp Reference]   0   0   0
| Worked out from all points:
|   slope of the pulldown table from 0 to 0.495 V, typ, clamps not added: 11.6 ohm
|   slope of the pullup table from 0 to 0.495 V, typ, clamps not added: 11.6 ohm
|   falling waveform, V_fixture 3.3V, R_fixture 50Ohm: 20-80 % time 518ps typ, 913ps min, 296ps max; typ from 3.3 V to 0.639 V
|   rising waveform, V_fixture 0V, R_fixture 50Ohm: 20-80 % time 674ps typ, 1.29ns min, 349ps max; typ from 0 V to 2.67 V
|   rising waveform, V_fixture 3.3V, R_fixture 50Ohm: 20-80 % time 152ps typ, 226ps min, 116ps max; typ from 0.639 V to 3.3 V
|   falling waveform, V_fixture 0V, R_fixture 50Ohm: 20-80 % time 184ps typ, 278ps min, 132ps max; typ from 2.67 V to 0.001 V
[Pulldown]
|   Voltage   I(typ)   I(min)   I(max)
-3.3V     -319.9mA   -216.5mA   -445.5mA
189mV     17.58mA    11.85mA    24.51mA
462mV     40.27mA    27mA       56.22mA
775.2mV   62.22mA    41.4mA     87.06mA
1.056V    78.05mA    51.51mA    109.5mA
1.251V    86.82mA    56.93mA    122mA
1.596V    97.13mA    63.25mA    135.8mA
2.165V    103mA      67.59mA    142mA
4.032V    107.5mA    70.78mA    147.8mA
6.6V      107.5mA    70.78mA    147.8mA
[GND Clamp]
|   Voltage   I(typ)   I(min)   I(max)
-3.3V     -1.553A    -1.315A    -1.789A
-1.214V   -75.2mA    -58.77mA   -96.04mA
-1.133V   -62.06mA   -49.14mA   -79.22mA
-1.033V   -46.78mA   -37.93mA   -59.46mA
-940.5mV  -33.68mA   -28.26mA   -42.33mA
-876mV    -25.29mA   -22mA      -31.29mA
-663mV    -4.673mA   -5.695mA   -4.527mA
-643.2mV  -3.575mA   -4.674mA   -3.252mA
-330mV    -4.518uA   -17.28uA   -5.664uA
6.6V      0A         0A         0A
[Pullup]
|   Voltage   I(typ)   I(min)   I(max)
-3.3V     301mA      218.2mA    398.3mA
1.2mV     -109.4uA   -79.25uA   -144.7uA
459mV     -39.81mA   -28.44mA   -53.04mA
855mV     -70.54mA   -49.65mA   -94.7mA
1.251V    -97.42mA   -67.29mA   -132mA
1.899V    -131.4mA   -86.9mA    -182.2mA
2.237V    -143.2mA   -91.82mA   -202mA
2.565V    -150.5mA   -94.39mA   -216.4mA
3.032V    -157.2mA   -97.16mA   -229.8mA
3.633V    -163.4mA   -99.07mA   -241mA
4.3V      -164.7mA   -99.07mA   -247.6mA
6.6V      -164.7mA   -99.07mA   -247.6mA
[POWER Clamp]
|   Voltage   I(typ)   I(min)   I(max)
-3.3V     1.469A     1.283A     1.789A
-1.219V   185.1mA    209mA      179.1mA
-1.136V   137.8mA    168.8mA    120.5mA
-1.068V   100mA      136.4mA    75.26mA
-1.007V   68.16mA    108.2mA    40.34mA
-973.5mV  52.09mA    93.27mA    25.99mA
-942mV    38.22mA    79.55mA    17.05mA
-867.9mV  14.43mA    49.44mA    9.533mA
-768mV    5.044mA    18.06mA    5.581mA
-720mV    3.634mA    9.339mA    4.032mA
-606mV    1.373mA    2.011mA    1.268mA
6.6V      0A         0A         0A
[Ramp]
R_load = 50
|   typ   min   max
dV/dt_r   1.60249/6.72929e-10   1.34184/1.2904e-09   1.83912/3.48116e-10
dV/dt_f   1.59655/5.16912e-10   1.30331/9.1199e-10   1.85171/2.95139e-10
[Falling Waveform]
V_fixture = 3.3V
V_fixture_min = 3V
V_fixture_max = 3.6V
R_fixture = 50Ohm
|   Time   V(typ)   V(min)   V(max)
0s        3.3V       3V         3.6V
884ps     3.301V     3V         3.424V
956ps     3.304V     3V         3.184V
1.274ns   3.044V     2.999V     1.15V
1.676ns   1.564V     2.957V     626.5mV
2.012ns   988.9mV    2.694V     567.1mV
2.22ns    845.6mV    2.209V     550.2mV
2.892ns   705.6mV    1.333V     526.3mV
3.604ns   667mV      1.004V     518.2mV
9.998ns   639mV      827.8mV    513.7mV
[Rising Waveform]
V_fixture = 0V
V_fixture_min = 0V
V_fixture_max = 0V
R_fixture = 50Ohm
|   Time   V(typ)   V(min)   V(max)
0s        1.479nV    67.62nV    785pV
828ps     639.8uV    67.62nV    22.97mV
880ps     818.9uV    -6.958uV   237.5mV
1.048ns   -13.7mV    16.89uV    1.654V
1.17ns    226.7mV    707.1uV    2.212V
1.44ns    1.33V      -15.29mV   2.702V
1.78ns    1.986V     300.4mV    2.935V
2.582ns   2.52V      1.368V     3.032V
3.764ns   2.63V      2.023V     3.057V
9.998ns   2.671V     2.236V     3.065V
[Rising Waveform]
V_fixture = 3.3V
V_fixture_min = 3V
V_fixture_max = 3.6V
R_fixture = 50Ohm
|   Time   V(typ)   V(min)   V(max)
0s        638.9mV    826.8mV    513.7mV
790ps     639.1mV    826.8mV    563.1mV
838ps     639.3mV    826.8mV    888.1mV
972ps     651.2mV    826.9mV    3.002V
1.066ns   896.7mV    826.9mV    3.337V
1.154ns   1.884V     826.6mV    3.448V
1.344ns   3.091V     837.7mV    3.558V
1.47ns    3.204V     992.5mV    3.583V
1.892ns   3.286V     2.854V     3.594V
3.088ns   3.297V     2.992V     3.598V
[Falling Waveform]
V_fixture = 0V
V_fixture_min = 0V
V_fixture_max = 0V
R_fixture = 50Ohm
|   Time   V(typ)   V(min)   V(max)
0s        2.671V     2.241V     3.065V
826ps     2.671V     2.241V     2.878V
906ps     2.674V     2.241V     2.402V
1.06ns    2.591V     2.241V     358.1mV
1.148ns   2.42V      2.241V     53.01mV
1.394ns   522.1mV    2.244V     6.041mV
1.52ns    81.26mV    2.22V      4.345mV
1.77ns    8.745mV    1.89V      2.625mV
2.224ns   3.019mV    108.7mV    1.379mV
3.03ns    1.188mV    3.151mV    435.5uV
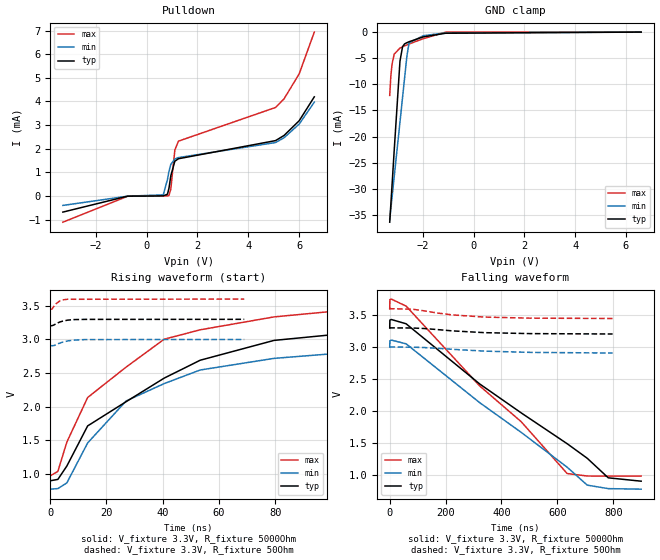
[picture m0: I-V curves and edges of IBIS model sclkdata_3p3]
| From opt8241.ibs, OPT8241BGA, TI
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|   sclkdata_3p3 Model
[Model]   sclkdata_3p3
Model_type   I/O_open_drain
Polarity   Inverting
Vinl = 0.99
Vinh = 2.31
Vmeas = 1.65
Vref = 3.3
Cref = 2pF
Rref = 5000
|   typ   min   max
|   (nom PVT)   (fast PVT)   (slow PVT)
C_comp   1.487e-12   1.014e-12   1.822e-12
[Model spec]
|subparameter
Vinl   0.99   0.90   1.08
Vinh   2.31   2.10   2.52
| Where nom  PVT is Nominal Process, 3.3V, 27C
|   Fast PVT is Strong Process,  3.6V, -40C
|   Slow PVT is Weak Process,   3V, 125C
[Voltage Range]   3.3   3   3.6
|Junction Temperature
[Temperature Range]   27   125   -40
[Pullup Reference]   3.3   3   3.6
[Pulldown Reference]   0   0   0
[Power Clamp Reference]   3.3   3   3.6
[GND Clamp Reference]   0   0   0
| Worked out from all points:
|   falling waveform, V_fixture 3.3V, R_fixture 5000Ohm: 20-80 % time 461ns typ, 406ns min, 373ns max; typ from 3.3 V to 0.901 V
|   rising waveform, V_fixture 3.3V, R_fixture 5000Ohm: 20-80 % time 52.3ns typ, 42.9ns min, 40.8ns max; typ from 0.901 V to 3.29 V
|   falling waveform, V_fixture 3.3V, R_fixture 50Ohm: 20-80 % time 202ns typ, 242ns min, 178ns max; typ from 3.3 V to 3.21 V
|   rising waveform, V_fixture 3.3V, R_fixture 50Ohm: 20-80 % time 3.67ns typ, 4.27ns min, 2.22ns max; typ from 3.21 V to 3.3 V
[Pulldown]
|   Voltage   I(typ)   I(min)   I(max)
-3.3V     -684.7uA   -402.2uA   -1.112mA
-751.2mV  -10.66uA   -10.49uA   -14.64uA
652.8mV   189.7nA    45.25uA    223.6pA
818.4mV   74.31uA    694.2uA    1.079uA
879mV     330.3uA    1.041mA    19.26uA
950.4mV   851.2uA    1.336mA    289.1uA
1.109V    1.469mA    1.561mA    1.941mA
1.251V    1.574mA    1.623mA    2.319mA
5.074V    2.341mA    2.259mA    3.744mA
5.409V    2.559mA    2.462mA    4.109mA
6.006V    3.183mA    3.042mA    5.17mA
6.6V      4.194mA    3.968mA    6.935mA
[GND Clamp]
|   Voltage   I(typ)   I(min)   I(max)
-3.3V     -36.4mA    -35.87mA   -12.12mA
-3.255V   -32.9mA    -33.79mA   -8.337mA
-3.204V   -28.96mA   -31.44mA   -6.012mA
-3.124V   -22.68mA   -27.71mA   -4.221mA
-2.897V   -5.586mA   -17.25mA   -3.065mA
-2.795V   -2.792mA   -12.52mA   -2.825mA
-2.716V   -2.264mA   -8.856mA   -2.648mA
-2.623V   -2.029mA   -4.584mA   -2.451mA
-2.541V   -1.853mA   -2.114mA   -2.281mA
-1.982V   -921uA     -689uA     -1.269mA
-1.1V     -220.7uA   -148.9uA   -6.034uA
6.6V      0A         0A         0A
[POWER Clamp]
|   Voltage   I(typ)   I(min)   I(max)
-3.3V     0A         0A         0A
0V        0A         0A         0A
6.6V      0A         0A         0A
[Ramp]
R_load = 5000
|   typ   min   max
dV/dt_r   1.43899/5.27535e-08   1.33369/4.36471e-08   1.57511/4.10469e-08
dV/dt_f   1.43941/4.61445e-07   1.33431/4.06144e-07   1.57108/3.73189e-07
[Falling Waveform]
V_fixture = 3.3V
V_fixture_min = 3V
V_fixture_max = 3.6V
R_fixture = 5000Ohm
|   Time   V(typ)   V(min)   V(max)
0s        3.3V       3V         3.6V
500ps     3.423V     3.099V     3.744V
5.6ns     3.433V     3.111V     3.753V
58.6ns    3.366V     3.052V     3.643V
321.9ns   2.424V     2.131V     2.393V
470.4ns   1.971V     1.666V     1.833V
635ns     1.488V     1.12V      1.021V
706.8ns   1.26V      839.3mV    982.1mV
782.1ns   953.7mV    784.6mV    980.8mV
899.9ns   901mV      776.1mV    981.5mV
[Rising Waveform]
V_fixture = 3.3V
V_fixture_min = 3V
V_fixture_max = 3.6V
R_fixture = 5000Ohm
|   Time   V(typ)   V(min)   V(max)
0s        900.9mV    776mV      974.3mV
2.7ns     921mV      784.7mV    1.04V
5.9ns     1.12V      869.5mV    1.476V
13.3ns    1.716V     1.463V     2.138V
27ns      2.076V     2.087V     2.59V
40.5ns    2.425V     2.344V     3.003V
53.3ns    2.691V     2.546V     3.143V
79.6ns    2.986V     2.719V     3.335V
131.1ns   3.195V     2.889V     3.538V
268.5ns   3.29V      2.987V     3.594V
[Falling Waveform]
V_fixture = 3.3V
V_fixture_min = 3V
V_fixture_max = 3.6V
R_fixture = 50Ohm
|   Time   V(typ)   V(min)   V(max)
0s        3.3V       3V         3.6V
200ps     3.306V     3.004V     3.608V
700ps     3.302V     3.003V     3.602V
79.6ns    3.3V       2.999V     3.595V
122.7ns   3.292V     2.994V     3.569V
171ns     3.275V     2.982V     3.534V
223.9ns   3.255V     2.966V     3.505V
338.8ns   3.227V     2.938V     3.471V
501.7ns   3.212V     2.918V     3.454V
797.7ns   3.206V     2.908V     3.449V
[Rising Waveform]
V_fixture = 3.3V
V_fixture_min = 3V
V_fixture_max = 3.6V
R_fixture = 50Ohm
|   Time   V(typ)   V(min)   V(max)
0s        3.205V     2.908V     3.448V
600ps     3.204V     2.907V     3.451V
1.3ns     3.215V     2.909V     3.493V
1.9ns     3.23V      2.919V     3.525V
3.3ns     3.258V     2.945V     3.57V
4.3ns     3.271V     2.959V     3.587V
6.2ns     3.287V     2.978V     3.598V
8.4ns     3.295V     2.99V      3.597V
12.3ns    3.298V     2.998V     3.597V
69ns      3.299V     2.999V     3.6V
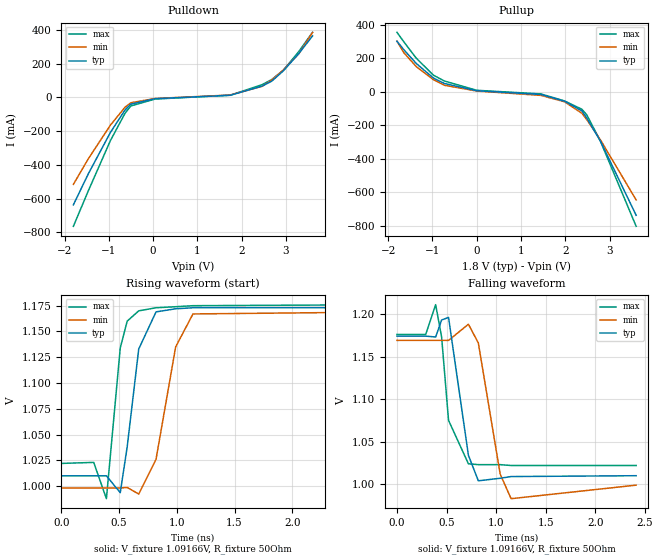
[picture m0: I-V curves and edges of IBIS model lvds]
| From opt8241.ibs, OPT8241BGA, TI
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|   lvds Model
[Model]   lvds
Model_type   Output
Polarity   Non-Inverting
Vmeas = 1.09166
Vref = 1.09166
Cref = 2pF
Rref = 50
|   typ   min   max
|   (nom PVT)   (fast PVT)   (slow PVT)
C_comp   3.584e-12   3.478e-12   3.809e-12
| Where nom  PVT is Nominal Process, 1.8V, 27C
|   Fast PVT is Strong Process,  1.9V, -40C
|   Slow PVT is Weak Process,   1.7V, 125C
[Voltage Range]   1.8   1.7   1.9
|Junction Temperature
[Temperature Range]   27   125   -40
[Pullup Reference]   1.8   1.7   1.9
[Pulldown Reference]   0   0   0
[Power Clamp Reference]   1.8   1.7   1.9
[GND Clamp Reference]   0   0   0
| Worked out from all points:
|   slope of the pulldown table from 0 to 0.27 V, typ, clamps not added: 62.2 ohm
|   slope of the pullup table from 0 to 0.27 V, typ, clamps not added: 59.3 ohm
|   falling waveform, V_fixture 1.09166V, R_fixture 50Ohm: 20-80 % time 95.4ps typ, 127ps min, 75.3ps max; typ from 1.17 V to 1.01 V
|   rising waveform, V_fixture 1.09166V, R_fixture 50Ohm: 20-80 % time 111ps typ, 159ps min, 85.5ps max; typ from 1.01 V to 1.17 V
[Pulldown]
|   Voltage   I(typ)   I(min)   I(max)
-1.8V     -636.6mA   -515.3mA   -763.6mA
-1.46V    -451.6mA   -362.7mA   -551.9mA
-963.6mV  -207.7mA   -164.4mA   -255.8mA
-633.6mV  -74.51mA   -58.08mA   -94.16mA
-504.6mV  -40.33mA   -32.03mA   -51.03mA
43mV      -7.759mA   -6.478mA   -9.985mA
1.741V    12.41mA    14.02mA    12.83mA
2.465V    67.35mA    65.7mA     76.02mA
2.678V    95.92mA    103.1mA    105.7mA
2.938V    156.5mA    161.6mA    160.3mA
3.288V    259.4mA    258mA      271.3mA
3.6V      364.1mA    384.8mA    385.6mA
[Pullup]
|   Voltage   I(typ)   I(min)   I(max)
-1.8V     301.8mA    301.9mA    355mA
-1.645V   251.1mA    233.3mA    298.2mA
-1.363V   168.6mA    149.9mA    200.2mA
-975.4mV  81.56mA    71.72mA    98.6mA
-727.2mV  49.06mA    38.34mA    63.92mA
300uV     5.937mA    4.281mA    8.642mA
1.447V    -16.32mA   -21.8mA    -13.02mA
1.982V    -56.61mA   -59.73mA   -54.8mA
2.375V    -114.2mA   -128.4mA   -104.6mA
2.486V    -157.4mA   -166.7mA   -138.3mA
2.79V     -293.3mA   -285.9mA   -293.4mA
3.6V      -738mA     -646.2mA   -803.6mA
[Ramp]
R_load = 50
|   typ   min   max
dV/dt_r   0.0972989/9.19791e-11  0.0963884/1.15675e-10  0.0917635/7.45433e-11
dV/dt_f   0.0984411/9.52975e-11   0.102469/1.26984e-10  0.0925798/7.50414e-11
[Falling Waveform]
V_fixture = 1.09166V
V_fixture_min = 1.08363V
V_fixture_max = 1.09889V
R_fixture = 50Ohm
|   Time   V(typ)   V(min)   V(max)
0s        1.174V     1.169V     1.176V
290ps     1.174V     1.169V     1.176V
390ps     1.173V     1.169V     1.211V
450ps     1.193V     1.169V     1.173V
520ps     1.196V     1.169V     1.075V
720ps     1.034V     1.188V     1.024V
820ps     1.004V     1.166V     1.023V
1.04ns    1.007V     1.012V     1.023V
1.15ns    1.009V     983mV      1.022V
2.41ns    1.01V      998.9mV    1.022V
[Rising Waveform]
V_fixture = 1.09166V
V_fixture_min = 1.08363V
V_fixture_max = 1.09889V
R_fixture = 50Ohm
|   Time   V(typ)   V(min)   V(max)
0s        1.01V      998.2mV    1.022V
280ps     1.01V      998.2mV    1.023V
390ps     1.01V      998.2mV    987.8mV
510ps     993.6mV    998.2mV    1.134V
570ps     1.038V     998.7mV    1.16V
670ps     1.133V     992.3mV    1.17V
820ps     1.169V     1.026V     1.173V
990ps     1.172V     1.135V     1.174V
1.14ns    1.173V     1.167V     1.175V
2.93ns    1.173V     1.169V     1.176V
